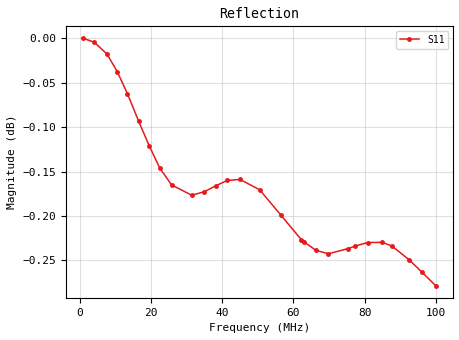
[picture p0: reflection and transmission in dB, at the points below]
# MHz S RI R 50.0
! SimSmith 18.4g
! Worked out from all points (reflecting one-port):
!   1000 points, 1 MHz to 100 MHz, reference 50 ohm
!   lowest |S11| = -0.3 dB at 100 MHz (marker M1), VSWR 62.41, Z = 0.889 + j16.6 ohm
!   phase of S11 starts at -9 deg and turns -927 deg over the sweep
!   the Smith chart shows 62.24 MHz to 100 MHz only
!   S11 on the Smith chart (normalised r, x): 62.24 MHz: 0.02, +0.40; 69.87 MHz: 0.05, +1.58; 77.41 MHz: 5, -19; 84.94 MHz: 0.04, -1.28; 92.47 MHz: 0.02, -0.30; 100 MHz: 0.02, +0.33
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1  0.9867 -0.1626
4.072072  0.7861 -0.6173
7.63964  0.3146 -0.9471
10.51351  -0.1497 -0.9844
13.38739  -0.5795 -0.8062
16.55856  -0.9009 -0.4088
19.53153  -0.9842 0.062
22.50451  -0.8376 0.5151
25.77478  -0.4558 0.8689
31.42342  0.4181 0.8862
34.99099  0.8369 0.5105
38.16216  0.9806 0.0301
41.43243  0.8604 -0.4728
45  0.4588 -0.8681
50.54955  -0.4006 -0.895
56.59459  -0.9648 -0.1558
62.24324  -0.703 0.6745
62.93694  -0.622 0.7495
66.40541  -0.122 0.9652
69.87387  0.4145 0.8797
75.32432  0.9447 0.2334
77.40541  0.9689 -0.0939
80.87387  0.7685 -0.5982
84.93694  0.2383 -0.9443
87.71171  -0.1984 -0.953
92.46847  -0.808 -0.5398
96.13514  -0.9701 0.00952
100  -0.7763 0.579
